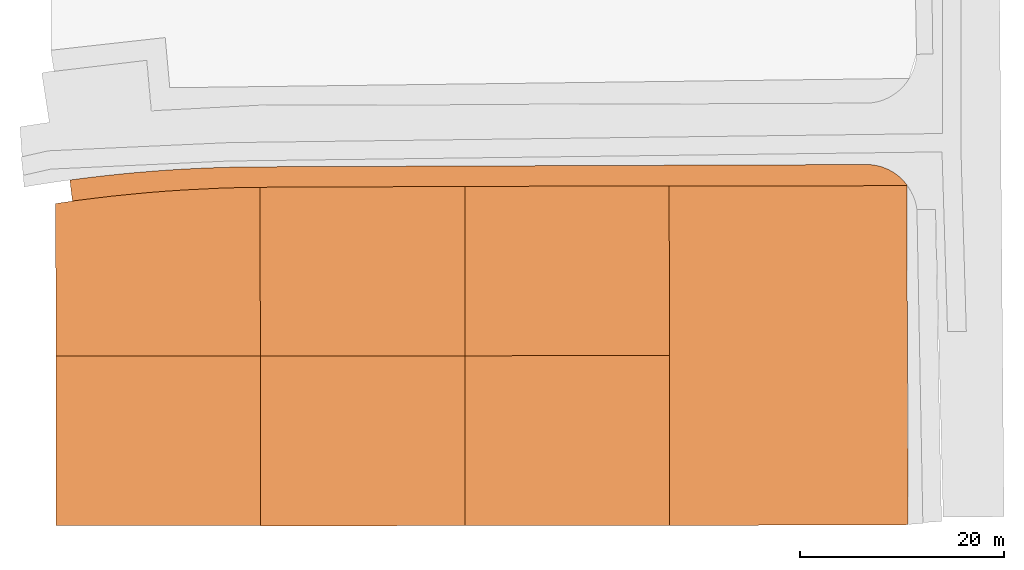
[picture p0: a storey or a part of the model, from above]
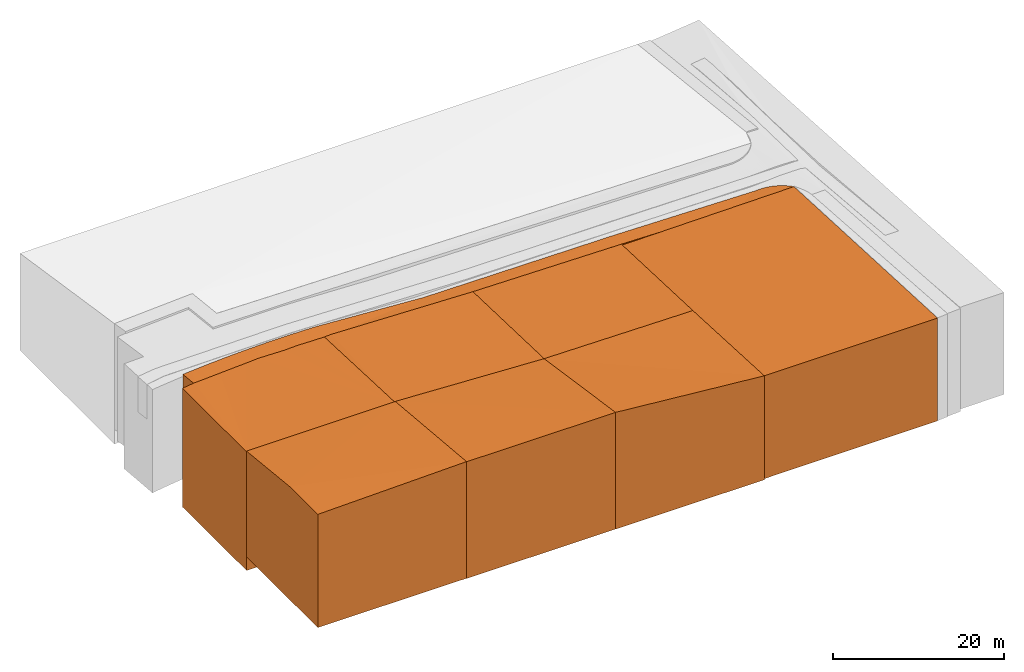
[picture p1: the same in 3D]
Properties of the parts of a building model (IFC4)

# File
Description: ViewDefinition [Design_Transfer_View, QuantityTakeOffAddOnView, SpaceBoundary2ndLevelAddOnView], ExchangeRequirement [Architecture], Option [Drawing Scale: 100.000000], Option [Elements to export: Visible elements (on all stories)], Option [Partial Structure Display: Entire Model], Option [IFC Domain: Custom], Option [Structural Function: All Elements], Option [Convert Grid elements: On], Option [Convert IFC Annotations and ARCHICAD 2D elements: Off], Option [Convert 2D symbols of Doors and Windows: Off], Option [Export geometries that Participates in Collision Detection only: Off], Option [Split complex elements: Off], Option [Material Preservation: Explode where necessary], Option [Elements in Solid Element Operations: Extruded/revolved], Option [Elements with junctions: Extruded/revolved without junctions], Option [Slabs with slanted edge(s): Extruded], Option [IFC Site Location: At Project Origin], Option [Curtain Wall export mode: Container Element], Option [Railing export mode: Single Element], Option [Stair export mode: Container Element], Option [Properties To Export: All properties], Option [Space containment: On], Option [IFC Domain For Space Containment: All], Option [Bounding Box: Off], Option [Geometry to type objects: Off], Option [Element Properties: All], Option [Building Material Properties: On], Option [Element Parameters: All], Option [Component Parameters: All], Option [IFC Base Quantities: On], Option [Door Window Parameters: On], Option [IFC Space boundaries: On], Option [ARCHICAD Zone Categories as IFC Space classification data: On], Option [Element Classifications: On]
File name: C:\Users\Eric\Desktop\education nationale\cap CRCTP\reseauxEU.ifc
Time: 2021-09-08T16:33:28
Author: Architect
Organization: Building Designer Office
Written by: The EXPRESS Data Manager Version 5.02.0100.09 : 26 Sep 2013
Made in: IFC file generated by GRAPHISOFT ARCHICAD 24.0.0 FRA FULL Windows version (IFC add-on version: 3008 FRA FULL).
Authorization: The authorising person

# IfcSite, Site
RefLatitude: 48, 52, 0, 0; RefLongitude: 2, 20, 0, 0; RefElevation: 26 m
Qto_SiteBaseQuantities - GrossPerimeter: 0 m; GrossArea: 0 m2

# IfcBuilding, Bâtiment
Qto_BuildingBaseQuantities - GrossFloorArea: 0 m2

# IfcBuildingStorey, 0. Etage
In: Bâtiment
Elevation: 0 m
Qto_BuildingStoreyBaseQuantities - NetHeight: 3.1 m; GrossHeight: 3.1 m; GrossFloorArea: 0 m2

# IfcGeographicElement: Env. - Terre (16)
In: Site
Classification: Géométrie du site (Classification ARCHICAD); Material: Env. - Terre
ArchiCADProperties - Matériau de construction / Composite / Profil / Hachure: Env. - Terre; Matériau de construction: Env. - Terre; Verrouillé: no; Nom d'étage d'implantation: 0. Etage; Numéro d'étage d'implantation: 0; Type d'élément: Maillage; Matériaux de construction (Tous): Env. - Terre; Nombre de percements: 0; Fonction structurelle: Non défini; Position: Extérieur; Etat de rénovation: Existant; Affichage sur filtre de rénovation: Tous les filtres appropriés; Surface inférieure: Env. - Terre; Type de Maillage: avec jupe; Classification ARCHICAD - 22: Géométrie du site
ArchiCADQuantities - Périmètre trous Plan: 0 m; Superficie des trous: 0 m2
Name | ID de l'élément = Lien et ID d'élément = ID de Parent | Calque | Surfaces (Toutes) | Hachure de recouvrement | Surface latérale = Surface supérieure | Superficie (m2) = Superficie inférieure (m2) | Hauteur (m) = Niveau de la jupe (m) | Volume net (m3) | Altitude à Zéro du Projet (m) = Altitude à étage lié/étage d'implantation (m) = Décalage étage d'implantation (m) | Altitude de Etage 1 (m) | Altitude de Toiture (m) | Altitude à niveau de la mer (m) | Superficie en plan (m2) = Superficie supérieure (m2) | Périmètre Plan (m) | Altitude supérieure à premier niveau de référence (m) | Altitude supérieure à étage d'implantation (m) = Altitude supérieure à Zéro du projet (m) | Altitude supérieure à niveau de la mer (m) | Altitude supérieure à deuxième niveau de référence (m) | Altitude inférieure à premier niveau de référence (m) | Altitude inférieure à étage d'implantation (m) = Altitude inférieure à Zéro du projet (m) | Altitude inférieure à niveau de la mer (m) | Altitude inférieure à deuxième niveau de référence (m) | Superficie d'arête (m2)
TERRAIN-002 | TERRAIN-002 | copie terrain original | Env. - Terre ; Brique - couleur de surface | 50 % | Brique - couleur de surface | 40.5892 | 20 | 478.522 | 44.3241 | 41.5241 | 38.7241 | 70.3241 | 40.7586 | 52.5542 | 34.451 | 37.251 | 63.251 | 31.651 | 21.5241 | 24.3241 | 50.3241 | 18.7241 | 620.065
TERRAIN-006 | TERRAIN-006 | copie terrain original | Env. - Terre ; Env. - Herbe fleurie | 25 % | Env. - Herbe fleurie | 333.861 | 20 | 4780.02 | 44.1732 | 41.3732 | 38.5732 | 70.1732 | 334.279 | 73.4217 | 36.365 | 39.165 | 65.165 | 33.565 | 21.3732 | 24.1732 | 50.1732 | 18.5732 | 1051.03
TERRAIN-006 | TERRAIN-006 | copie terrain original | Env. - Terre ; Env. - Herbe fleurie | 25 % | Env. - Herbe fleurie | 334.791 | 20 | 5323.02 | 44.1732 | 41.3732 | 38.5732 | 70.1732 | 336.058 | 73.5017 | 38.0392 | 40.8392 | 66.8392 | 35.2392 | 21.3732 | 24.1732 | 50.1732 | 18.5732 | 1162.54
TERRAIN-001 | TERRAIN-001 | copie terrain original | Env. - Terre ; Brique - couleur de surface | 50 % | Brique - couleur de surface | 38.5939 | 20 | 540.74 | 44.3241 | 41.5241 | 38.7241 | 70.3241 | 38.9036 | 68.2729 | 36.2189 | 39.0189 | 65.0189 | 33.4189 | 21.5241 | 24.3241 | 50.3241 | 18.7241 | 954.149
TERRAIN-001 | TERRAIN-001 | copie terrain original | Env. - Terre ; Brique - couleur de surface | 50 % | Brique - couleur de surface | 182.851 | 20 | 2554.29 | 44.3241 | 41.5241 | 38.7241 | 70.3241 | 183.525 | 180.548 | 36.6391 | 39.4391 | 65.4391 | 33.8391 | 21.5241 | 24.3241 | 50.3241 | 18.7241 | 2530.23
TERRAIN-012 | TERRAIN-012 | copie terrain original | Env. - Terre ; Env. - Herbe fleurie | 25 % | Env. - Herbe fleurie | 334.835 | 20 | 4637.28 | 44.1732 | 41.3732 | 38.5732 | 70.1732 | 335.063 | 73.5134 | 35.5868 | 38.3868 | 64.3868 | 32.7868 | 21.3732 | 24.1732 | 50.1732 | 18.5732 | 1017.37
TERRAIN-001 | TERRAIN-001 | copie terrain original | Env. - Terre ; Brique - couleur de surface | 50 % | Brique - couleur de surface | 56.1924 | 20 | 785.169 | 44.3241 | 41.5241 | 38.7241 | 70.3241 | 56.2548 | 65.0812 | 36.2189 | 39.0189 | 65.0189 | 33.4189 | 21.5241 | 24.3241 | 50.3241 | 18.7241 | 909.293
TERRAIN-009 | TERRAIN-009 | copie terrain original | Env. - Terre ; Env. - Herbe fleurie | 25 % | Env. - Herbe fleurie | 321.628 | 20 | 5395.27 | 42.2292 | 39.4292 | 36.6292 | 68.2292 | 321.874 | 71.8064 | 36.365 | 39.165 | 65.165 | 33.565 | 19.4292 | 22.2292 | 48.2292 | 16.6292 | 1203.93
TERRAIN-006 | TERRAIN-006 | copie terrain original | Env. - Terre ; Env. - Herbe fleurie | 25 % | Env. - Herbe fleurie | 781.272 | 20 | 10875 | 44.3241 | 41.5241 | 38.7241 | 70.3241 | 782.098 | 113.578 | 36.2189 | 39.0189 | 65.0189 | 33.4189 | 21.5241 | 24.3241 | 50.3241 | 18.7241 | 1582.46
TERRAIN-001 | TERRAIN-001 | copie terrain original | Env. - Terre ; Brique - couleur de surface | 50 % | Brique - couleur de surface | 164.89 | 20 | 2253.79 | 44.3241 | 41.5241 | 38.7241 | 70.3241 | 165.578 | 167.255 | 36.4695 | 39.2695 | 65.2695 | 33.6695 | 21.5241 | 24.3241 | 50.3241 | 18.7241 | 2287.96
TERRAIN-011 | TERRAIN-011 | copie terrain original | Env. - Terre ; Env. - Herbe fleurie | 25 % | Env. - Herbe fleurie | 335.589 | 20 | 4968.56 | 44.1732 | 41.3732 | 38.5732 | 70.1732 | 338.274 | 73.5908 | 38.0424 | 40.8424 | 66.8424 | 35.2424 | 21.3732 | 24.1732 | 50.1732 | 18.5732 | 1099.69
TERRAIN-001 | TERRAIN-001 | copie terrain original | Env. - Terre ; Env. - Asphalte clair | 50 % | Env. - Asphalte clair | 1070.3 | 20 | 13365.9 | 44.3241 | 41.5241 | 38.7241 | 70.3241 | 827.048 | 338.509 | 36.533 | 39.333 | 65.333 | 33.733 | 21.5241 | 24.3241 | 50.3241 | 18.7241 | 4487.47
TERRAIN-013 | TERRAIN-013 | copie terrain original | Env. - Terre ; Env. - Herbe fleurie | 25 % | Env. - Herbe fleurie | 335.851 | 20 | 5291.47 | 44.1732 | 41.3732 | 38.5732 | 70.1732 | 338.526 | 73.6209 | 38.0424 | 40.8424 | 66.8424 | 35.2424 | 21.3732 | 24.1732 | 50.1732 | 18.5732 | 1154.15
TERRAIN-009 | TERRAIN-009 | copie terrain original | Env. - Terre ; Env. - Herbe fleurie | 25 % | Env. - Herbe fleurie | 2194.92 | 20 | 32695.5 | 42.2292 | 39.4292 | 36.6292 | 68.2292 | 2210.07 | 222.82 | 36.6326 | 39.4326 | 65.4326 | 33.8326 | 19.4292 | 22.2292 | 48.2292 | 16.6292 | 3284.67
TERRAIN-010 | TERRAIN-010 | FOND DE TRANCHEE | Env. - Terre ; Peinture - Oxyde plomb jaune | 25 % | Peinture - Oxyde plomb jaune | 245.163 | 17.2735 | 495.434 | 51.4804 | 48.6804 | 45.8804 | 77.4804 | 245.807 | 273.705 | 35.2063 | 38.0063 | 64.0063 | 32.4063 | 31.4069 | 34.2069 | 60.2069 | 28.6069 | 553.385
DEBLAI TRANCHÉE | DEBLAI TRANCHÉE | DEBLAI TRANCHÉE | Env. - Terre ; Env. - Ecorce tronc | 25 % | Env. - Ecorce tronc | 245.163 | 18.5106 | 818.329 | 52.7175 | 49.9175 | 47.1175 | 78.7175 | 246.395 | 273.705 | 36.4433 | 39.2433 | 65.2433 | 33.6433 | 31.4069 | 34.2069 | 60.2069 | 28.6069 | 914.994

# IfcPipeSegment: Béton armé (Coulé) D300 (10)
In: 0. Etage
Classification: Tronçon de tuyauterie (Classification ARCHICAD); Material: Béton armé (Coulé)
ArchiCADProperties - ID de l'élément: CANALISATION EU; Lien et ID d'élément: CANALISATION EU; Calque: canalisation EU; Matériau de construction / Composite / Profil / Hachure: Béton armé (Coulé); Matériau de construction: Béton armé (Coulé); Verrouillé: no; Nom d'étage d'implantation: 0. Etage; Numéro d'étage d'implantation: 0; Type d'élément: Poteau; Etage supérieur lié absolu: Non lié; Etage supérieur lié relatif: Non lié; Etage supérieur lié: Non lié; Type de structure: Basique; ID de Parent: CANALISATION EU; Matériaux de construction (Tous): Béton armé (Coulé); Surfaces (Toutes): Béton - Brut; Hachure de recouvrement: Sans Trame; Fonction structurelle: Non défini; Position: Non défini; Etat de rénovation: Existant; Affichage sur filtre de rénovation: Tous les filtres appropriés; Coupe transversale de Poteau: Circulaire; Surface d'extrusion: Béton - Brut; Surface de fin: Béton - Brut; Génération de modèle analytique structurel: yes; Classification ARCHICAD - 22: Tronçon de tuyauterie
Component Properties - Component 1, Type de composant: Ame
ArchiCADQuantities - Largeur: 0.3 m; Décalage supérieur: -0.2 m; Hauteur coupe transversale haut/fin (perpendiculaire): 0.3 m; Hauteur coupe transversale bas/départ (perpendiculaire): 0.3 m; Largeur coupe transversale haut/fin (perpendiculaire): 0.3 m; Largeur coupe transversale bas/départ (perpendiculaire): 0.3 m; Hauteur coupe transversale haut/fin (coupée): 0.3 m; Hauteur coupe transversale bas/départ (coupée): 0.3 m; Largeur coupe transversale haut/fin (coupée): 0.3 m; Largeur coupe transversale bas/départ (coupée): 0.3 m; Surface coupe transversale bas/départ (coupée): 0.0700941 m2; Surface coupe transversale haut/fin: 0.0700941 m2; Nombre de segments: 1; Hauteur / Diamètre d'âme: 0.3 m; Largeur d'âme: 0.3 m; Superficie brute au sommet de l'âme: 0.0700941 m2; Superficie brute inférieure à la base de l'âme: 0.0700941 m2; Superficie brute du Revêtement (sans haut/bas): 0 m2; Superficie brute du sommet du revêtement: 0 m2; Superficie brute de la base du revêtement: 0 m2; Volume brut du Revêtement: 0 m3; Superficie nette du bas de l'Âme: 0.0700941 m2; Superficie nette du haut de l'Âme: 0.0700941 m2; Superficie nette du bas du Revêtement: 0 m2; Superficie du Revêtement: 0 m2; Superficie nette du haut du Revêtement: 0 m2; Périmètre de profil de poteau (base): 0.942478 m; Volume net du Revêtement: 0 m3
Component Quantities - Component 1, Epaisseur couche: 0.3 m; Component 1, Superficie de coupe transversale de composant: 0.0706858 m2
Name | Angle d'inclinaison (deg) = Angle d'inclinaison de Poteau (deg) | Component 1, Empreinte carbone | Component 1, Energie grise (MJ) | Superficie (m2) | Hauteur (m) | Volume net (m3) = Volume brut (m3) = Volume net de l'Âme (m3) = Volume brut de l'Âme (m3) = Component 1, Volume de couche/composant (m3) | Altitude à Zéro du Projet (m) = Altitude à étage lié/étage d'implantation (m) = Décalage étage d'implantation (m) | Altitude de Etage 1 (m) | Altitude de Toiture (m) | Altitude à niveau de la mer (m) | Superficie en plan (m2) = Superficie brute de l'Âme (sans haut/bas) (m2) = Superficie nette de l'Âme (sans haut/bas) (m2) | Longueur 3D (m) | Altitude supérieure à premier niveau de référence (m) | Altitude supérieure à étage d'implantation (m) = Altitude supérieure à Zéro du projet (m) | Altitude supérieure à niveau de la mer (m) | Altitude supérieure à deuxième niveau de référence (m) | Altitude inférieure à premier niveau de référence (m) | Altitude inférieure à étage d'implantation (m) = Altitude inférieure à Zéro du projet (m) | Altitude inférieure à niveau de la mer (m) | Altitude inférieure à deuxième niveau de référence (m) | Component 1, Masse (kg)
CANALISATION EU | 2 | 365.447 (kgCO₂) | 3543.73 | 0.00244625 | 0.399548 | 0.802475 | 35.7401 | 32.9401 | 30.1401 | 61.7401 | 10.7674 | 11.4485 | 33.4896 | 36.2896 | 62.2896 | 30.6896 | 32.7902 | 35.5902 | 61.5902 | 29.9902 | 1845.69
CANALISATION EU | 1 | 710.96 (kgCO₂) | 6894.16 | 0.00122331 | 0.38871 | 1.56118 | 35.9419 | 33.1419 | 30.3419 | 61.9419 | 20.9474 | 22.2726 | 33.6806 | 36.4806 | 62.4806 | 30.8806 | 32.9919 | 35.7919 | 61.7919 | 30.1919 | 3590.71
CANALISATION EU | 1 | 743.091 (kgCO₂) | 7205.73 | 0.00122331 | 0.406277 | 1.63173 | 36.3775 | 33.5775 | 30.7775 | 62.3775 | 21.8941 | 23.2792 | 34.1338 | 36.9338 | 62.9338 | 31.3338 | 33.4276 | 36.2276 | 62.2276 | 30.6276 | 3752.98
CANALISATION EU | 1 | 109.097 (kgCO₂) | 1057.91 | 0.00122331 | 0.0596475 | 0.239562 | 37.0116 | 34.2116 | 31.4116 | 63.0116 | 3.21437 | 3.41772 | 34.4212 | 37.2212 | 63.2212 | 31.6212 | 34.0616 | 36.8616 | 62.8616 | 31.2616 | 550.993
CANALISATION EU | 2 | 732.643 (kgCO₂) | 7104.41 | 0.00244625 | 0.801008 | 1.60879 | 34.8373 | 32.0373 | 29.2373 | 60.8373 | 21.5863 | 22.9519 | 32.9882 | 35.7882 | 61.7882 | 30.1882 | 31.8874 | 34.6874 | 60.6874 | 29.0874 | 3700.22
CANALISATION EU | 1 | 441.789 (kgCO₂) | 4284.01 | 0.00122331 | 0.241544 | 0.970111 | 37.1995 | 34.3995 | 31.5995 | 63.1995 | 13.0167 | 13.8401 | 34.7911 | 37.5911 | 63.5911 | 31.9911 | 34.2496 | 37.0496 | 63.0496 | 31.4496 | 2231.26
CANALISATION EU | 2 | 738.043 (kgCO₂) | 7156.78 | 0.00244625 | 0.806913 | 1.62065 | 36.853 | 34.053 | 31.253 | 62.853 | 21.7454 | 23.121 | 35.0098 | 37.8098 | 63.8098 | 32.2098 | 33.9031 | 36.7031 | 62.7031 | 31.1031 | 3727.49
CANALISATION EU | 2 | 529.562 (kgCO₂) | 5135.14 | 0.00244625 | 0.578977 | 1.16285 | 37.8622 | 35.0622 | 32.2622 | 63.8622 | 15.6028 | 16.5898 | 35.7911 | 38.5911 | 64.5911 | 32.9911 | 34.9123 | 37.7123 | 63.7123 | 32.1123 | 2674.55
CANALISATION EU | 2 | 108.744 (kgCO₂) | 1054.49 | 0.00244625 | 0.118892 | 0.238789 | 37.7635 | 34.9635 | 32.1635 | 63.7635 | 3.204 | 3.40669 | 35.2323 | 38.0323 | 64.0323 | 32.4323 | 34.8136 | 37.6136 | 63.6136 | 32.0136 | 549.214
CANALISATION EU | 1 | 102.727 (kgCO₂) | 996.144 | 0.00122331 | 0.0561651 | 0.225576 | 37.2682 | 34.4682 | 31.6682 | 63.2682 | 3.02671 | 3.21819 | 34.6743 | 37.4743 | 63.4743 | 31.8743 | 34.3182 | 37.1182 | 63.1182 | 31.5182 | 518.825

# IfcPipeSegment: Volume - Etude (4)
In: 0. Etage
Classification: Tronçon de tuyauterie (Classification ARCHICAD); Material: Volume - Etude
ArchiCADProperties - Calque: REGARD EU; Matériau de construction / Composite / Profil / Hachure: Volume - Etude; Matériau de construction: Volume - Etude; Verrouillé: no; Nom d'étage d'implantation: 0. Etage; Numéro d'étage d'implantation: 0; Type d'élément: Forme; Matériaux de construction (Tous): Volume - Etude; Surfaces (Toutes): Volume - Maquette blanche; Fonction structurelle: Non défini; Position: Non défini; Etat de rénovation: Existant; Classification par DIN 277: Non défini; Affichage sur filtre de rénovation: Tous les filtres appropriés; Ombres portées: yes; Ombrage reçu: yes; Surface: Volume - Maquette blanche; Classification ARCHICAD - 22: Tronçon de tuyauterie
Component Properties - Component 1, Empreinte carbone: 0 (kgCO₂); Component 1, Energie grise: 0 MJ; Component 1, Type de composant: Aucun
ArchiCADQuantities - Superficie: 0.779927 m2; Périmètre Plan: 3.13461 m
Component Quantities - Component 1, Masse: 0 kg
Name | ID de l'élément = Lien et ID d'élément = ID de Parent | Volume net (m3) = Component 1, Volume de couche/composant (m3) | Altitude à Zéro du Projet (m) = Altitude à étage lié/étage d'implantation (m) = Décalage étage d'implantation (m) = Altitude inférieure à étage d'implantation (m) = Altitude inférieure à Zéro du projet (m) | Altitude de Etage 1 (m) = Altitude inférieure à premier niveau de référence (m) | Altitude de Toiture (m) = Altitude inférieure à deuxième niveau de référence (m) | Altitude à niveau de la mer (m) = Altitude inférieure à niveau de la mer (m) | Superficie en plan (m2) | Altitude supérieure à premier niveau de référence (m) | Altitude supérieure à étage d'implantation (m) = Altitude supérieure à Zéro du projet (m) | Altitude supérieure à niveau de la mer (m) | Altitude supérieure à deuxième niveau de référence (m)
REGARD EU3 N5 | REGARD EU3 N5 | 0.285335 | 37.316 | 34.516 | 31.716 | 63.316 | 9.52105 | 35.896 | 38.696 | 64.696 | 33.096
REGARD EU3 N6 | REGARD EU3 N6 | 0.285335 | 36.4517 | 33.6517 | 30.8517 | 62.4517 | 9.52105 | 35.0316 | 37.8316 | 63.8316 | 32.2316
REGARD EU3 N7 | REGARD EU3 N7 | 0.285335 | 36.1382 | 33.3382 | 30.5382 | 62.1382 | 9.52105 | 34.7181 | 37.5181 | 63.5181 | 31.9181
REGARD EU3 N8 | REGARD EU3 N8 | 0.326064 | 35.472 | 32.672 | 29.872 | 61.472 | 10.8237 | 34.2737 | 37.0737 | 63.0737 | 31.4737

# IfcWall: Béton armé (Apparent) 250 (3)
In: 0. Etage
Classification: Mur (Classification ARCHICAD); Material: Béton armé (Apparent) 0.25 m
ArchiCADProperties - ID de l'élément: MUR_EXT-001; Lien et ID d'élément: MUR_EXT-001; Calque: COMPTEUR; Matériau de construction / Composite / Profil / Hachure: Béton armé (Apparent); Matériau de construction: Béton armé (Apparent); Verrouillé: no; Nom d'étage d'implantation: 0. Etage; Numéro d'étage d'implantation: 0; Type d'élément: Mur; Etage supérieur lié absolu: Non lié; Etage supérieur lié relatif: Non lié; Etage supérieur lié: Non lié; Type de structure: Basique; ID de Parent: MUR_EXT-001; Matériaux de construction (Tous): Béton armé (Apparent); Surfaces (Toutes): Appareillage - Pierre taillé; Angle d'inclinaison: 90 deg; Nombre de percements: 0; Fonction structurelle: Elément porteur; Position: Extérieur; Etat de rénovation: Existant; Affichage sur filtre de rénovation: Tous les filtres appropriés; Complexité de mur: Droit; Option de géométrie: Uniforme; Emplacement de ligne de référence: Centrer; Surface latérale: Appareillage - Pierre taillé; Surface de face intérieure: Appareillage - Pierre taillé; Surface de face extérieure: Appareillage - Pierre taillé; Angle d'inclinaison interne de mur: 90 deg; Angle d'inclinaison externe de mur: 90 deg; Génération de modèle analytique structurel: yes; Classification ARCHICAD - 22: Mur
Pset_WallCommon - LoadBearing: yes; IsExternal: yes; Status: EXISTING
Component Properties - Component 1, Empreinte carbone: 267.305 (kgCO₂); Component 1, Energie grise: 2592.05 MJ; Component 1, Type de composant: Aucun
Qto_WallBaseQuantities - Length: 1.56525 m; Height: 1.5 m; Width: 0.25 m; GrossFootprintArea: 0.391311 m2; NetFootprintArea: 0.391311 m2; GrossSideArea: 2.34787 m2; NetSideArea: 2.34787 m2; GrossVolume: 0.586967 m3; NetVolume: 0.586967 m3; Component 1, Width: 0.25 m
ArchiCADQuantities - Superficie: 0.391311 m2; Hauteur: 1.5 m; Volume net: 0.586967 m3; Largeur: 0.25 m; Décalage supérieur: 0 m; Superficie en plan: 2.34787 m2; Longueur 3D: 1.56525 m; Epaisseur: 0.25 m; Volume conditionnel: 0.586967 m3; Volume brut: 0.586967 m3; Epaisseur couche isolation: 0 m; Périmètre Plan: 3.63049 m; Nombre de Portes: 0; Nombre de trous (Nombre d'ouvertures vides): 0; Nombre de Fenêtres: 0; Nombre de Poteaux: 0; Volume des poteaux: 0 m3; Hauteur maximale de la couche de Mur sur face intérieure: 0 m; Hauteur minimale de la couche de Mur sur face intérieure: 0 m; Hauteur maximale du Mur: 1.5 m; Hauteur minimale du Mur: 1.5 m; Hauteur maximale de la couche de Mur sur face extérieure: 0 m; Hauteur minimale de la couche de Mur sur face extérieure: 0 m; Epaisseur couche d'air: 0 m; Superficie des portes: 0 m2; Largeur totale des Portes: 0 m; Epaisseur de couche de Mur sur face intérieure: 0 m; Epaisseur de couche de Mur sur face extérieure: 0 m; Superficie des fenêtres: 0 m2; Largeur totale des Fenêtres: 0 m; Superficie analytique des ouvertures sur face intérieure: 0 m2; Superficie analytique des ouvertures sur face extérieure: 0 m2; Longueur moyenne du mur: 1.56525 m; Superficie nette des arêtes: 1.53262 m2; Superficie nette de Mur sur face intérieure: 2.34787 m2; Superficie nette de Mur sur face extérieure: 2.34787 m2; Volume analytique des ouvertures: 0 m3; Longueur de ligne de référence: 1.56525 m; Longueur conditionnelle sur face intérieure: 1.56525 m; Superficie conditionnelle sur face intérieure: 2.34787 m2; Longueur conditionnelle sur face extérieure: 1.56525 m; Superficie conditionnelle sur face extérieure: 2.34787 m2; Superficie brute de Mur sur face intérieure: 2.34787 m2; Superficie brute de Mur sur face extérieure: 2.34787 m2; Epaisseur du Mur à la fin: 0.25 m; Longueur du Mur au centre: 1.56525 m; Longueur de Mur sur face intérieure: 1.56525 m; Longueur de Mur sur face extérieure: 1.56525 m; Superficie des baies libres dans le Mur: 0 m2
Component Quantities - Component 1, Masse: 1350.02 kg; Component 1, Superficie projetée de composant/couche: 2.34787 m2; Component 1, Epaisseur couche: 0.25 m; Component 1, Hauteur de composant rectangulaire: 1.5 m; Component 1, Largeur de composant rectangulaire: 0.25 m; Component 1, Superficie de coupe transversale de composant: 0.375 m2; Component 1, Volume de couche/composant: 0.586967 m3
Name | Altitude à Zéro du Projet (m) = Altitude à étage lié/étage d'implantation (m) = Décalage étage d'implantation (m) = Altitude inférieure à étage d'implantation (m) = Altitude inférieure à Zéro du projet (m) | Altitude de Etage 1 (m) = Altitude inférieure à premier niveau de référence (m) | Altitude de Toiture (m) = Altitude inférieure à deuxième niveau de référence (m) | Altitude à niveau de la mer (m) = Altitude inférieure à niveau de la mer (m) | Altitude supérieure à premier niveau de référence (m) | Altitude supérieure à étage d'implantation (m) = Altitude supérieure à Zéro du projet (m) | Altitude supérieure à niveau de la mer (m) | Altitude supérieure à deuxième niveau de référence (m)
MUR_EXT-001 | 37.7932 | 34.9932 | 32.1932 | 63.7932 | 36.4932 | 39.2932 | 65.2932 | 33.6932
MUR_EXT-001 | 38.2738 | 35.4738 | 32.6738 | 64.2738 | 36.9738 | 39.7738 | 65.7738 | 34.1738
MUR_EXT-001 | 38.593 | 35.793 | 32.993 | 64.593 | 37.293 | 40.093 | 66.093 | 34.493

# IfcWall: Béton armé (Apparent) 50 (6)
In: 0. Etage
Classification: Mur (Classification ARCHICAD); Material: Béton armé (Apparent) 0.05 m
ArchiCADProperties - Calque: COMPTEUR; Matériau de construction / Composite / Profil / Hachure: Béton armé (Apparent); Matériau de construction: Béton armé (Apparent); Verrouillé: no; Nom d'étage d'implantation: 0. Etage; Numéro d'étage d'implantation: 0; Type d'élément: Mur; Etage supérieur lié absolu: Non lié; Etage supérieur lié relatif: Non lié; Etage supérieur lié: Non lié; Type de structure: Basique; Matériaux de construction (Tous): Béton armé (Apparent); Surfaces (Toutes): Déco - Cuir blanc; Angle d'inclinaison: 90 deg; Nombre de percements: 0; Fonction structurelle: Elément porteur; Position: Extérieur; Etat de rénovation: Existant; Affichage sur filtre de rénovation: Tous les filtres appropriés; Complexité de mur: Droit; Option de géométrie: Uniforme; Emplacement de ligne de référence: Centrer; Surface latérale: Déco - Cuir blanc; Surface de face intérieure: Déco - Cuir blanc; Surface de face extérieure: Déco - Cuir blanc; Angle d'inclinaison interne de mur: 90 deg; Angle d'inclinaison externe de mur: 90 deg; Génération de modèle analytique structurel: yes; Classification ARCHICAD - 22: Mur
Pset_WallCommon - LoadBearing: yes; IsExternal: yes; Status: EXISTING
Component Properties - Component 1, Type de composant: Aucun
Qto_WallBaseQuantities - Height: 0.455679 m; Width: 0.05 m; Component 1, Width: 0.05 m
ArchiCADQuantities - Hauteur: 0.455679 m; Largeur: 0.05 m; Décalage supérieur: 0 m; Epaisseur: 0.05 m; Epaisseur couche isolation: 0 m; Nombre de Portes: 0; Nombre de trous (Nombre d'ouvertures vides): 0; Nombre de Fenêtres: 0; Nombre de Poteaux: 0; Volume des poteaux: 0 m3; Hauteur maximale de la couche de Mur sur face intérieure: 0 m; Hauteur minimale de la couche de Mur sur face intérieure: 0 m; Hauteur maximale du Mur: 0.455679 m; Hauteur minimale du Mur: 0.455679 m; Hauteur maximale de la couche de Mur sur face extérieure: 0 m; Hauteur minimale de la couche de Mur sur face extérieure: 0 m; Epaisseur couche d'air: 0 m; Superficie des portes: 0 m2; Largeur totale des Portes: 0 m; Epaisseur de couche de Mur sur face intérieure: 0 m; Epaisseur de couche de Mur sur face extérieure: 0 m; Superficie des fenêtres: 0 m2; Largeur totale des Fenêtres: 0 m; Superficie analytique des ouvertures sur face intérieure: 0 m2; Superficie analytique des ouvertures sur face extérieure: 0 m2; Volume analytique des ouvertures: 0 m3; Epaisseur du Mur à la fin: 0.05 m; Superficie des baies libres dans le Mur: 0 m2
Component Quantities - Component 1, Epaisseur couche: 0.05 m; Component 1, Hauteur de composant rectangulaire: 0.455679 m; Component 1, Largeur de composant rectangulaire: 0.05 m; Component 1, Superficie de coupe transversale de composant: 0.0227839 m2
Name | ID de l'élément = Lien et ID d'élément = ID de Parent | Component 1, Empreinte carbone | Component 1, Energie grise (MJ) | Length (m) = Longueur 3D (m) = Longueur moyenne du mur (m) = Longueur de ligne de référence (m) = Longueur conditionnelle sur face intérieure (m) = Longueur conditionnelle sur face extérieure (m) = Longueur du Mur au centre (m) = Longueur de Mur sur face intérieure (m) = Longueur de Mur sur face extérieure (m) | GrossFootprintArea (m2) = NetFootprintArea (m2) = Superficie (m2) | GrossSideArea (m2) = NetSideArea (m2) = Superficie en plan (m2) = Superficie nette de Mur sur face intérieure (m2) = Superficie nette de Mur sur face extérieure (m2) = Superficie conditionnelle sur face intérieure (m2) = Superficie conditionnelle sur face extérieure (m2) = Superficie brute de Mur sur face intérieure (m2) = Superficie brute de Mur sur face extérieure (m2) = Component 1, Superficie projetée de composant/couche (m2) | GrossVolume (m3) = NetVolume (m3) = Volume net (m3) = Volume conditionnel (m3) = Volume brut (m3) = Component 1, Volume de couche/composant (m3) | Altitude à Zéro du Projet (m) = Altitude à étage lié/étage d'implantation (m) = Décalage étage d'implantation (m) = Altitude inférieure à étage d'implantation (m) = Altitude inférieure à Zéro du projet (m) | Altitude de Etage 1 (m) = Altitude inférieure à premier niveau de référence (m) | Altitude de Toiture (m) = Altitude inférieure à deuxième niveau de référence (m) | Altitude à niveau de la mer (m) = Altitude inférieure à niveau de la mer (m) | Périmètre Plan (m) | Altitude supérieure à premier niveau de référence (m) | Altitude supérieure à étage d'implantation (m) = Altitude supérieure à Zéro du projet (m) | Altitude supérieure à niveau de la mer (m) | Altitude supérieure à deuxième niveau de référence (m) | Superficie nette des arêtes (m2) | Component 1, Masse (kg)
MUR_EXT-002 | MUR_EXT-002 | 4.1358 (kgCO₂) | 40.1047 | 0.3986 | 0.01993 | 0.181634 | 0.00908168 | 38.4095 | 35.6095 | 32.8095 | 64.4095 | 0.8972 | 36.0652 | 38.8652 | 64.8652 | 33.2652 | 0.0854279 | 20.8879
MUR_EXT-003 | MUR_EXT-003 | 4.55889 (kgCO₂) | 44.2074 | 0.439377 | 0.0219688 | 0.200215 | 0.0100107 | 38.4095 | 35.6095 | 32.8095 | 64.4095 | 0.978754 | 36.0652 | 38.8652 | 64.8652 | 33.2652 | 0.0895056 | 23.0247
MUR_EXT-002 | MUR_EXT-002 | 4.1358 (kgCO₂) | 40.1047 | 0.3986 | 0.01993 | 0.181634 | 0.00908168 | 38.8901 | 36.0901 | 33.2901 | 64.8901 | 0.8972 | 36.5457 | 39.3457 | 65.3457 | 33.7457 | 0.0854279 | 20.8879
MUR_EXT-003 | MUR_EXT-003 | 4.55889 (kgCO₂) | 44.2074 | 0.439377 | 0.0219688 | 0.200215 | 0.0100107 | 38.8901 | 36.0901 | 33.2901 | 64.8901 | 0.978754 | 36.5457 | 39.3457 | 65.3457 | 33.7457 | 0.0895056 | 23.0247
MUR_EXT-002 | MUR_EXT-002 | 4.1358 (kgCO₂) | 40.1047 | 0.3986 | 0.01993 | 0.181634 | 0.00908168 | 39.2093 | 36.4093 | 33.6093 | 65.2093 | 0.8972 | 36.865 | 39.665 | 65.665 | 34.065 | 0.0854279 | 20.8879
MUR_EXT-003 | MUR_EXT-003 | 4.55889 (kgCO₂) | 44.2074 | 0.439377 | 0.0219688 | 0.200215 | 0.0100107 | 39.2093 | 36.4093 | 33.6093 | 65.2093 | 0.978754 | 36.865 | 39.665 | 65.665 | 34.065 | 0.0895056 | 23.0247

# Material: Béton armé (Apparent)
Pset_MaterialThermal - ThermalConductivity: 2.3; SpecificHeatCapacity: 1000 J/kg/K
Pset_MaterialCommon - MassDensity: 2300 kg/m3
AC_Pset_MaterialCustom - Embodied Energy: 1.92 (MJ/kg); Embodied Carbon: 0.198 (kgCO₂/kg); Participates in Collision Detection: yes

# Material: Volume - Etude
Pset_MaterialThermal - ThermalConductivity: 0; SpecificHeatCapacity: 0 J/kg/K
Pset_MaterialCommon - MassDensity: 0 kg/m3
AC_Pset_MaterialCustom - Embodied Energy: 0 (MJ/kg); Embodied Carbon: 0 (kgCO₂/kg); Participates in Collision Detection: yes

# Material: Béton armé (Coulé)
Pset_MaterialThermal - ThermalConductivity: 2.3; SpecificHeatCapacity: 1000 J/kg/K
Pset_MaterialCommon - MassDensity: 2300 kg/m3
AC_Pset_MaterialCustom - Embodied Energy: 1.92 (MJ/kg); Embodied Carbon: 0.198 (kgCO₂/kg); Participates in Collision Detection: yes

# Material: Env. - Terre
Pset_MaterialThermal - ThermalConductivity: 1.4; SpecificHeatCapacity: 1400 J/kg/K
Pset_MaterialCommon - MassDensity: 1900 kg/m3
AC_Pset_MaterialCustom - Embodied Energy: 0.43 (MJ/kg); Embodied Carbon: 0.023 (kgCO₂/kg); Participates in Collision Detection: no
